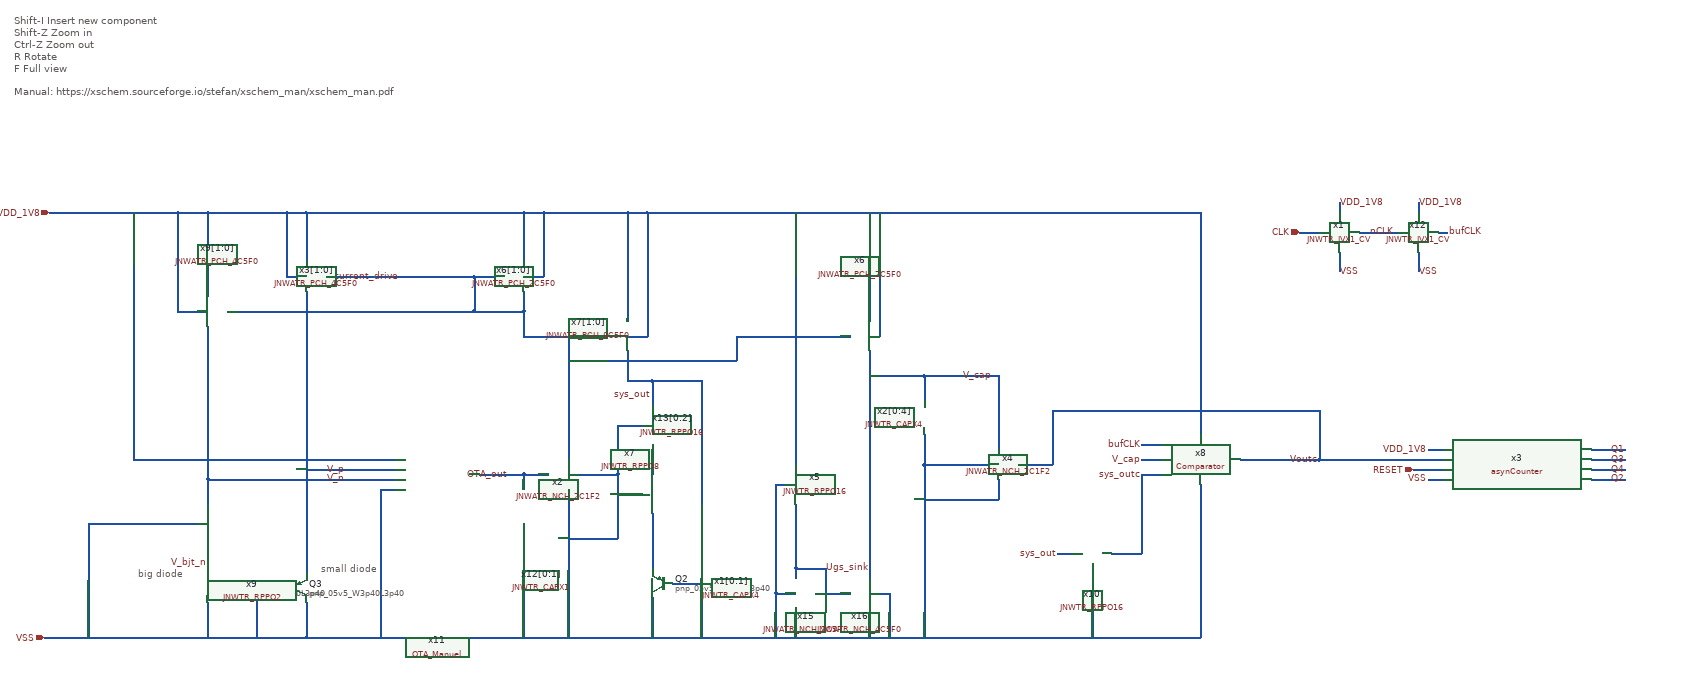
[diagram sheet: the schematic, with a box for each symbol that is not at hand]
v {xschem version=3.4.6 file_version=1.2}
G {}
K {}
V {}
S {}
E {}
T {Shift-I          Insert new component
Shift-Z         Zoom in
Ctrl-Z           Zoom out
R                 Rotate
F                 Full view

Manual: https://xschem.sourceforge.io/stefan/xschem_man/xschem_man.pdf
} -1500 -1380 0 0 0.6 0.6 {}
T {big diode
} -1250 -260 0 0 0.4 0.4 {}
T {small diode
} -880 -270 0 0 0.4 0.4 {}
N -1110 -310 -1110 -250 {
lab=V_bjt_n}
N -1010 -220 -950 -220 {
lab=VSS}
N -1110 -190 -1110 -120 {
lab=VSS}
N -910 -190 -910 -120 {
lab=VSS}
N -1010 -220 -1010 -120 {
lab=VSS}
N -1010 -120 -910 -120 {
lab=VSS}
N -1230 -120 -1110 -120 {
lab=VSS}
N -1110 -440 -1110 -390 {
lab=V_n}
N -910 -120 -830 -120 {
lab=VSS}
N -1110 -980 -950 -980 {
lab=VDD_1V8}
N -470 -450 -420 -450 {
lab=OTA_out}
N -380 -450 -340 -450 {
lab=VSS}
N -910 -980 -470 -980 {
lab=VDD_1V8}
N -470 -980 -430 -980 {
lab=VDD_1V8}
N -380 -730 -380 -480 {
lab=V_current_drive}
N -470 -980 -470 -880 {
lab=VDD_1V8}
N -470 -850 -430 -850 {
lab=VDD_1V8}
N -430 -980 -430 -850 {
lab=VDD_1V8}
N -570 -850 -570 -780 {
lab=V_current_drive}
N -1260 -980 -1260 -480 {
lab=VDD_1V8}
N -1430 -980 -1170 -980 {
lab=VDD_1V8}
N -910 -980 -910 -880 {
lab=VDD_1V8}
N -950 -980 -950 -850 {
lab=VDD_1V8}
N -570 -850 -510 -850 {
lab=V_current_drive}
N -950 -850 -910 -850 {
lab=VDD_1V8}
N -260 -700 -260 -640 {
lab=sys_out}
N -430 -980 -260 -980 {
lab=VDD_1V8}
N -260 -730 -220 -730 {
lab=VDD_1V8}
N -260 -980 -220 -980 {
lab=VDD_1V8}
N -470 -730 -300 -730 {
lab=V_current_drive}
N -570 -780 -470 -780 {
lab=V_current_drive}
N -1170 -780 -1110 -780 {
lab=VDD_1V8}
N -1170 -980 -1170 -780 {
lab=VDD_1V8}
N -1110 -980 -1110 -810 {
lab=VDD_1V8}
N -260 -980 -260 -760 {
lab=VDD_1V8}
N -220 -980 -220 -730 {
lab=VDD_1V8}
N -1230 -350 -1130 -350 {
lab=VSS}
N -1350 -350 -1350 -120 {
lab=VSS}
N -470 -350 -470 -300 {
lab=VSS}
N -470 -450 -470 -420 {
lab=OTA_out}
N -1070 -220 -1010 -220 {
lab=VSS}
N -1110 -120 -1010 -120 {
lab=VSS}
N -380 -420 -380 -340 {
lab=VSS}
N -870 -850 -570 -850 {
lab=V_current_drive}
N -1070 -780 -570 -780 {
lab=V_current_drive}
N -470 -820 -470 -780 {
lab=V_current_drive}
N -950 -980 -910 -980 {
lab=VDD_1V8}
N -470 -780 -470 -730 {
lab=V_current_drive}
N -1170 -980 -1110 -980 {
lab=VDD_1V8}
N -1260 -120 -1230 -120 {
lab=VSS}
N -830 -460 -800 -460 {
lab=V_p}
N -910 -820 -910 -250 {
lab=V_p}
N -830 -440 -800 -440 {
lab=V_n}
N -1110 -440 -830 -440 {
lab=V_n}
N -910 -460 -830 -460 {
lab=V_p}
N -210 -370 -210 -320 {
lab=#net1}
N -830 -120 -340 -120 {
lab=VSS}
N -470 -300 -470 -120 {
lab=VSS}
N -1440 -120 -1260 -120 {lab=VSS}
N -1350 -350 -1230 -350 {lab=VSS}
N -1260 -480 -800 -480 {lab=VDD_1V8}
N -560 -450 -470 -450 {lab=OTA_out}
N -800 -480 -730 -480 {lab=VDD_1V8}
N -800 -460 -730 -460 {lab=V_p}
N -800 -440 -730 -440 {lab=V_n}
N -760 -420 -740 -420 {lab=VSS}
N -760 -420 -760 -120 {lab=VSS}
N -740 -420 -730 -420 {lab=VSS}
N -260 -640 -210 -640 {lab=sys_out}
N -210 -320 -210 -300 {lab=#net1}
N -340 -120 -50 -120 {lab=VSS}
N 230 -700 230 -600 {lab=V_cap}
N -380 -680 -140 -680 {lab=V_current_drive}
N 140 -730 190 -730 {lab=V_current_drive}
N -220 -980 -50 -980 {lab=VDD_1V8}
N 230 -980 230 -760 {lab=VDD_1V8}
N 230 -730 250 -730 {lab=VDD_1V8}
N 250 -980 250 -730 {lab=VDD_1V8}
N -50 -980 -30 -980 {lab=VDD_1V8}
N 350 -650 490 -650 {lab=V_cap}
N 490 -650 490 -500 {lab=V_cap}
N 350 -470 490 -470 {lab=VSS}
N 490 -440 490 -400 {lab=VSS}
N 350 -400 490 -400 {lab=VSS}
N 530 -470 590 -470 {lab=Voutc}
N -1110 -540 -1110 -440 {lab=V_n}
N 900 -980 900 -570 {lab=VDD_1V8}
N 370 -980 900 -980 {lab=VDD_1V8}
N 350 -120 900 -120 {lab=VSS}
N 900 -390 900 -120 {lab=VSS}
N -210 -300 -210 -260 {lab=#net1}
N -210 -200 -210 -120 {lab=VSS}
N -1110 -750 -1110 -540 {lab=V_n}
N -110 -470 -110 -390 {lab=sys_out}
N -110 -320 -110 -270 {lab=VSS}
N -210 -640 -210 -590 {lab=sys_out}
N -110 -640 -110 -470 {lab=sys_out}
N -210 -640 -110 -640 {lab=sys_out}
N -380 -340 -380 -120 {lab=VSS}
N -280 -360 -280 -320 {lab=VSS}
N -380 -320 -280 -320 {lab=VSS}
N -280 -410 -230 -410 {lab=VSS}
N -210 -510 -210 -450 {lab=#net2}
N -340 -450 -280 -450 {lab=VSS}
N -280 -450 -280 -360 {lab=VSS}
N 610 -290 640 -290 {lab=sys_out}
N 1100 -940 1140 -940 {lab=CLK}
N 1220 -940 1240 -940 {lab=nCLK}
N 1180 -1000 1180 -980 {lab=VDD_1V8}
N 1180 -900 1180 -860 {lab=VSS}
N 780 -400 780 -290 {lab=sys_outc}
N 1380 -940 1400 -940 {lab=bufCLK}
N 1240 -940 1300 -940 {lab=nCLK}
N 720 -290 780 -290 {lab=sys_outc}
N 680 -270 680 -120 {lab=VSS}
N 1340 -1000 1340 -980 {lab=VDD_1V8}
N 1340 -900 1340 -860 {lab=VSS}
N -280 -550 -230 -550 {lab=VSS}
N -280 -550 -280 -450 {lab=VSS}
N 900 -570 900 -530 {lab=VDD_1V8}
N 900 -430 900 -390 {lab=VSS}
N 980 -480 1140 -480 {lab=Voutc}
N 780 -510 820 -510 {lab=bufCLK}
N 780 -450 820 -450 {lab=sys_outc}
N 780 -480 820 -480 {lab=V_cap}
N 780 -450 780 -400 {lab=sys_outc}
N 1140 -580 1140 -480 {lab=Voutc}
N 600 -580 1140 -580 {lab=Voutc}
N 600 -580 600 -470 {lab=Voutc}
N 590 -470 600 -470 {lab=Voutc}
N 1360 -460 1390 -460 {lab=RESET}
N 1360 -440 1390 -440 {lab=VSS}
N 1360 -480 1390 -480 {lab=Voutc}
N 1360 -500 1390 -500 {lab=VDD_1V8}
N 1330 -460 1360 -460 {lab=RESET}
N 1140 -480 1360 -480 {lab=Voutc}
N 1690 -460 1760 -460 {lab=Q4}
N 1690 -500 1760 -500 {lab=Q1}
N 1690 -480 1760 -480 {lab=Q3}
N 1690 -440 1760 -440 {lab=Q2}
N -110 -270 -110 -120 {lab=VSS}
N -170 -230 -110 -230 {lab=VSS}
N -30 -980 370 -980 {lab=VDD_1V8}
N -50 -120 350 -120 {lab=VSS}
N 340 -650 350 -650 {lab=V_cap}
N 340 -650 340 -600 {lab=V_cap}
N 340 -530 340 -470 {lab=VSS}
N 340 -470 350 -470 {lab=VSS}
N 340 -470 340 -120 {lab=VSS}
N 340 -400 350 -400 {lab=VSS}
N 230 -650 340 -650 {lab=V_cap}
N -40 -730 140 -730 {lab=V_current_drive}
N -140 -680 -40 -680 {lab=V_current_drive}
N -40 -730 -40 -680 {lab=V_current_drive}
N 80 -180 80 -120 {lab=VSS}
N 230 -180 230 -120 {lab=VSS}
N 120 -210 150 -210 {lab=Ugs_sink}
N 140 -260 140 -210 {lab=Ugs_sink}
N 80 -260 80 -240 {lab=Ugs_sink}
N 80 -260 80 -240 {lab=Ugs_sink}
N 80 -260 140 -260 {lab=Ugs_sink}
N 150 -210 190 -210 {lab=Ugs_sink}
N 230 -210 270 -210 {lab=VSS}
N 270 -210 270 -120 {lab=VSS}
N 40 -210 40 -120 {lab=VSS}
N 40 -210 80 -210 {lab=VSS}
N 230 -600 230 -250 {lab=V_cap}
N 230 -250 230 -240 {lab=V_cap}
N 80 -390 80 -260 {lab=Ugs_sink}
N 40 -430 60 -430 {lab=VSS}
N 40 -430 40 -210 {lab=VSS}
N 80 -980 80 -470 {lab=VDD_1V8}
C {devices/ipin.sym} -1430 -980 0 0 {name=p1 lab=VDD_1V8}
C {devices/ipin.sym} -1440 -120 0 0 {name=p8 lab=VSS}
C {JNW_ATR_SKY130A/JNWATR_PCH_4C5F0.sym} -1070 -780 0 1 {name=x9[1:0]}
C {JNW_ATR_SKY130A/JNWATR_PCH_2C5F0.sym} -510 -850 0 0 {name=x6[1:0]}
C {JNW_ATR_SKY130A/JNWATR_PCH_8C5F0.sym} -300 -730 0 0 {name=x7[1:0]}
C {sky130_fd_pr/pnp_05v5.sym} -930 -220 0 0 {name=Q3
model=pnp_05v5_W3p40L3p40
m=1
spiceprefix=X
}
C {sky130_fd_pr/pnp_05v5.sym} -1090 -220 0 1 {name=Q1
model=pnp_05v5_W3p40L3p40
m=5
spiceprefix=X
}
C {devices/lab_wire.sym} -500 -450 0 0 {name=p10 sig_type=std_logic lab=OTA_out}
C {devices/lab_wire.sym} -720 -850 0 0 {name=p11 sig_type=std_logic lab=V_current_drive}
C {devices/lab_wire.sym} -830 -460 0 0 {name=p12 sig_type=std_logic lab=V_p}
C {devices/lab_wire.sym} -830 -440 0 0 {name=p13 sig_type=std_logic lab=V_n}
C {JNW_GR05_SKY130A/OTA_Manuel.sym} -580 -450 0 0 {name=x11}
C {devices/lab_wire.sym} -1110 -270 0 0 {name=p15 sig_type=std_logic lab=V_bjt_n}
C {JNW_ATR_SKY130A/JNWATR_NCH_2C1F2.sym} -420 -450 0 0 {name=x2 }
C {JNW_TR_SKY130A/JNWTR_RPPO2.sym} -1110 -390 1 0 {name=x9}
C {JNW_ATR_SKY130A/JNWATR_PCH_2C5F0.sym} 190 -730 0 0 {name=x6}
C {JNW_ATR_SKY130A/JNWATR_NCH_2C1F2.sym} 530 -470 0 1 {name=x4 }
C {devices/ipin.sym} 1330 -460 0 0 {name=p5 lab=RESET
}
C {JNW_TR_SKY130A/JNWTR_CAPX4.sym} 340 -540 0 0 {name=x2[0:4]}
C {devices/lab_wire.sym} -210 -610 0 0 {name=p7 sig_type=std_logic lab=sys_out}
C {JNW_GR05_SKY130A/Comparator.sym} 900 -480 0 0 {name=x8}
C {devices/lab_wire.sym} 480 -650 0 0 {name=p17 sig_type=std_logic lab=V_cap}
C {devices/lab_wire.sym} 780 -480 0 0 {name=p18 sig_type=std_logic lab=V_cap}
C {devices/lab_wire.sym} 610 -290 0 0 {name=p19 sig_type=std_logic lab=sys_out}
C {JNW_TR_SKY130A/JNWTR_CAPX1.sym} -470 -360 0 0 {name=x12[0:1]}
C {sky130_fd_pr/pnp_05v5.sym} -190 -230 0 1 {name=Q2
model=pnp_05v5_W3p40L3p40
m=1
spiceprefix=X
}
C {JNW_ATR_SKY130A/JNWATR_PCH_4C5F0.sym} -870 -850 0 1 {name=x3[1:0]}
C {JNW_TR_SKY130A/JNWTR_CAPX4.sym} -110 -330 0 0 {name=x1[0:1]}
C {JNW_TR_SKY130A/JNWTR_IVX1_CV.sym} 1140 -940 0 0 {name=x1 }
C {devices/lab_wire.sym} 1240 -940 0 1 {name=p6 sig_type=std_logic lab=nCLK}
C {devices/lab_wire.sym} 1180 -1000 0 1 {name=p21 sig_type=std_logic lab=VDD_1V8
}
C {devices/lab_wire.sym} 1180 -860 0 1 {name=p22 sig_type=std_logic lab=VSS
}
C {devices/lab_wire.sym} 1400 -940 0 1 {name=p27 sig_type=std_logic lab=bufCLK}
C {devices/lab_wire.sym} 780 -510 0 0 {name=p9 sig_type=std_logic lab=bufCLK}
C {JNW_TR_SKY130A/JNWTR_RPPO16.sym} 640 -290 0 0 {name=x10}
C {JNW_TR_SKY130A/JNWTR_IVX1_CV.sym} 1300 -940 0 0 {name=x12 }
C {devices/lab_wire.sym} 1340 -1000 0 1 {name=p26 sig_type=std_logic lab=VDD_1V8
}
C {devices/lab_wire.sym} 1340 -860 0 1 {name=p28 sig_type=std_logic lab=VSS
}
C {JNW_TR_SKY130A/JNWTR_RPPO8.sym} -210 -450 1 0 {name=x7}
C {JNW_TR_SKY130A/JNWTR_RPPO16.sym} -210 -590 1 0 {name=x13[0:2]}
C {devices/lab_wire.sym} 1140 -480 0 0 {name=p2 sig_type=std_logic lab=Voutc}
C {devices/ipin.sym} 1100 -940 0 0 {name=p14 lab=CLK
}
C {devices/lab_wire.sym} 780 -450 0 0 {name=p3 sig_type=std_logic lab=sys_outc}
C {JNW_GR05_SKY130A/asynCounter.sym} 1540 -470 0 0 {name=x3}
C {devices/lab_wire.sym} 1360 -440 0 0 {name=p4 sig_type=std_logic lab=VSS
}
C {devices/lab_pin.sym} 1360 -500 0 0 {name=p20 sig_type=std_logic lab=VDD_1V8
}
C {devices/lab_pin.sym} 1760 -440 0 0 {name=p16 sig_type=std_logic lab=Q2
}
C {devices/lab_pin.sym} 1760 -500 0 0 {name=p23 sig_type=std_logic lab=Q1
}
C {devices/lab_pin.sym} 1760 -480 0 0 {name=p24 sig_type=std_logic lab=Q3}
C {devices/lab_pin.sym} 1760 -460 0 0 {name=p25 sig_type=std_logic lab=Q4}
C {JNW_ATR_SKY130A/JNWATR_NCH_2C5F0.sym} 120 -210 0 1 {name=x15 }
C {JNW_ATR_SKY130A/JNWATR_NCH_4C5F0.sym} 190 -210 0 0 {name=x16 }
C {JNW_TR_SKY130A/JNWTR_RPPO16.sym} 80 -470 1 0 {name=x5}
C {devices/lab_wire.sym} 140 -260 0 1 {name=p29 sig_type=std_logic lab=Ugs_sink
}
